VERSION 5.7 ;
BUSBITCHARS "[]" ;
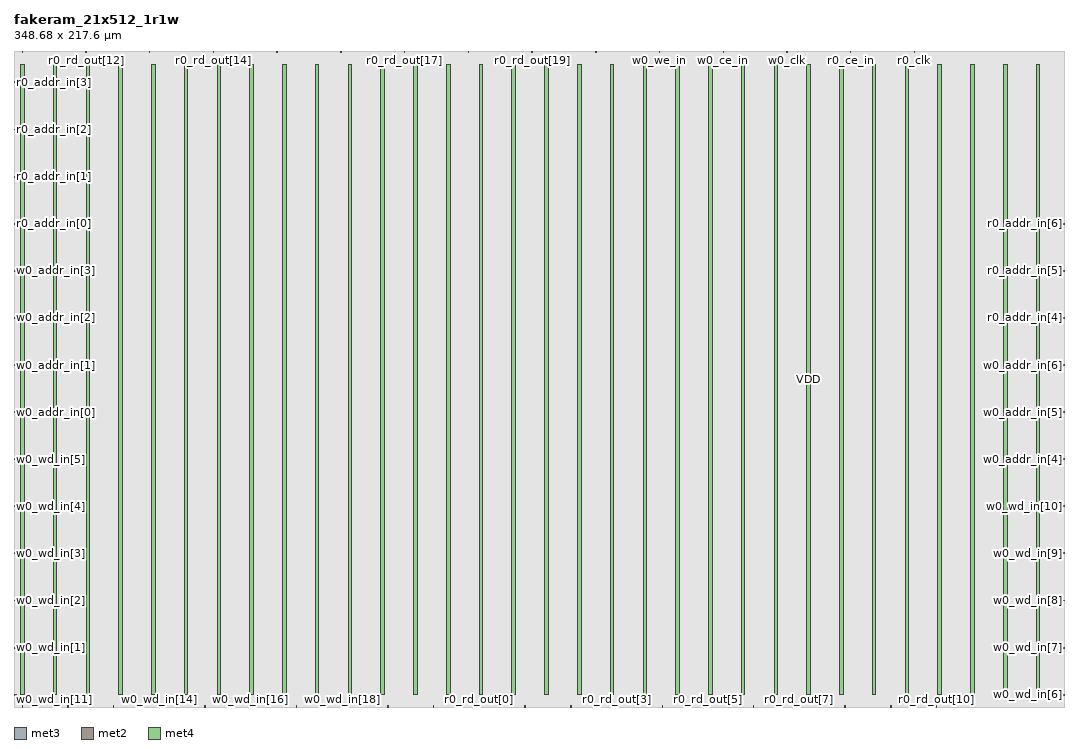
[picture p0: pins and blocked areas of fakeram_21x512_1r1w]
MACRO fakeram_21x512_1r1w
  FOREIGN fakeram_21x512_1r1w 0 0 ;
  SYMMETRY X Y R90 ;
  SIZE 348.680 BY 217.600 ;
  CLASS BLOCK ;
  PIN w0_wd_in[0]
    DIRECTION INPUT ;
    USE SIGNAL ;
    SHAPE ABUTMENT ;
    PORT
      LAYER met3 ;
      RECT 0.000 3.930 0.900 4.230 ;
    END
  END w0_wd_in[0]
  PIN w0_wd_in[1]
    DIRECTION INPUT ;
    USE SIGNAL ;
    SHAPE ABUTMENT ;
    PORT
      LAYER met3 ;
      RECT 0.000 19.570 0.900 19.870 ;
    END
  END w0_wd_in[1]
  PIN w0_wd_in[2]
    DIRECTION INPUT ;
    USE SIGNAL ;
    SHAPE ABUTMENT ;
    PORT
      LAYER met3 ;
      RECT 0.000 35.210 0.900 35.510 ;
    END
  END w0_wd_in[2]
  PIN w0_wd_in[3]
    DIRECTION INPUT ;
    USE SIGNAL ;
    SHAPE ABUTMENT ;
    PORT
      LAYER met3 ;
      RECT 0.000 50.850 0.900 51.150 ;
    END
  END w0_wd_in[3]
  PIN w0_wd_in[4]
    DIRECTION INPUT ;
    USE SIGNAL ;
    SHAPE ABUTMENT ;
    PORT
      LAYER met3 ;
      RECT 0.000 66.490 0.900 66.790 ;
    END
  END w0_wd_in[4]
  PIN w0_wd_in[5]
    DIRECTION INPUT ;
    USE SIGNAL ;
    SHAPE ABUTMENT ;
    PORT
      LAYER met3 ;
      RECT 0.000 82.130 0.900 82.430 ;
    END
  END w0_wd_in[5]
  PIN w0_wd_in[6]
    DIRECTION INPUT ;
    USE SIGNAL ;
    SHAPE ABUTMENT ;
    PORT
      LAYER met3 ;
      RECT 347.780 3.930 348.680 4.230 ;
    END
  END w0_wd_in[6]
  PIN w0_wd_in[7]
    DIRECTION INPUT ;
    USE SIGNAL ;
    SHAPE ABUTMENT ;
    PORT
      LAYER met3 ;
      RECT 347.780 19.570 348.680 19.870 ;
    END
  END w0_wd_in[7]
  PIN w0_wd_in[8]
    DIRECTION INPUT ;
    USE SIGNAL ;
    SHAPE ABUTMENT ;
    PORT
      LAYER met3 ;
      RECT 347.780 35.210 348.680 35.510 ;
    END
  END w0_wd_in[8]
  PIN w0_wd_in[9]
    DIRECTION INPUT ;
    USE SIGNAL ;
    SHAPE ABUTMENT ;
    PORT
      LAYER met3 ;
      RECT 347.780 50.850 348.680 51.150 ;
    END
  END w0_wd_in[9]
  PIN w0_wd_in[10]
    DIRECTION INPUT ;
    USE SIGNAL ;
    SHAPE ABUTMENT ;
    PORT
      LAYER met3 ;
      RECT 347.780 66.490 348.680 66.790 ;
    END
  END w0_wd_in[10]
  PIN w0_wd_in[11]
    DIRECTION INPUT ;
    USE SIGNAL ;
    SHAPE ABUTMENT ;
    PORT
      LAYER met2 ;
      RECT 2.690 0.000 2.830 0.420 ;
    END
  END w0_wd_in[11]
  PIN w0_wd_in[12]
    DIRECTION INPUT ;
    USE SIGNAL ;
    SHAPE ABUTMENT ;
    PORT
      LAYER met2 ;
      RECT 17.870 0.000 18.010 0.420 ;
    END
  END w0_wd_in[12]
  PIN w0_wd_in[13]
    DIRECTION INPUT ;
    USE SIGNAL ;
    SHAPE ABUTMENT ;
    PORT
      LAYER met2 ;
      RECT 33.050 0.000 33.190 0.420 ;
    END
  END w0_wd_in[13]
  PIN w0_wd_in[14]
    DIRECTION INPUT ;
    USE SIGNAL ;
    SHAPE ABUTMENT ;
    PORT
      LAYER met2 ;
      RECT 48.230 0.000 48.370 0.420 ;
    END
  END w0_wd_in[14]
  PIN w0_wd_in[15]
    DIRECTION INPUT ;
    USE SIGNAL ;
    SHAPE ABUTMENT ;
    PORT
      LAYER met2 ;
      RECT 63.410 0.000 63.550 0.420 ;
    END
  END w0_wd_in[15]
  PIN w0_wd_in[16]
    DIRECTION INPUT ;
    USE SIGNAL ;
    SHAPE ABUTMENT ;
    PORT
      LAYER met2 ;
      RECT 78.590 0.000 78.730 0.420 ;
    END
  END w0_wd_in[16]
  PIN w0_wd_in[17]
    DIRECTION INPUT ;
    USE SIGNAL ;
    SHAPE ABUTMENT ;
    PORT
      LAYER met2 ;
      RECT 93.770 0.000 93.910 0.420 ;
    END
  END w0_wd_in[17]
  PIN w0_wd_in[18]
    DIRECTION INPUT ;
    USE SIGNAL ;
    SHAPE ABUTMENT ;
    PORT
      LAYER met2 ;
      RECT 108.950 0.000 109.090 0.420 ;
    END
  END w0_wd_in[18]
  PIN w0_wd_in[19]
    DIRECTION INPUT ;
    USE SIGNAL ;
    SHAPE ABUTMENT ;
    PORT
      LAYER met2 ;
      RECT 124.130 0.000 124.270 0.420 ;
    END
  END w0_wd_in[19]
  PIN w0_wd_in[20]
    DIRECTION INPUT ;
    USE SIGNAL ;
    SHAPE ABUTMENT ;
    PORT
      LAYER met2 ;
      RECT 139.310 0.000 139.450 0.420 ;
    END
  END w0_wd_in[20]
  PIN r0_rd_out[0]
    DIRECTION OUTPUT ;
    USE SIGNAL ;
    SHAPE ABUTMENT ;
    PORT
      LAYER met2 ;
      RECT 154.490 0.000 154.630 0.420 ;
    END
  END r0_rd_out[0]
  PIN r0_rd_out[1]
    DIRECTION OUTPUT ;
    USE SIGNAL ;
    SHAPE ABUTMENT ;
    PORT
      LAYER met2 ;
      RECT 169.670 0.000 169.810 0.420 ;
    END
  END r0_rd_out[1]
  PIN r0_rd_out[2]
    DIRECTION OUTPUT ;
    USE SIGNAL ;
    SHAPE ABUTMENT ;
    PORT
      LAYER met2 ;
      RECT 184.850 0.000 184.990 0.420 ;
    END
  END r0_rd_out[2]
  PIN r0_rd_out[3]
    DIRECTION OUTPUT ;
    USE SIGNAL ;
    SHAPE ABUTMENT ;
    PORT
      LAYER met2 ;
      RECT 200.030 0.000 200.170 0.420 ;
    END
  END r0_rd_out[3]
  PIN r0_rd_out[4]
    DIRECTION OUTPUT ;
    USE SIGNAL ;
    SHAPE ABUTMENT ;
    PORT
      LAYER met2 ;
      RECT 215.210 0.000 215.350 0.420 ;
    END
  END r0_rd_out[4]
  PIN r0_rd_out[5]
    DIRECTION OUTPUT ;
    USE SIGNAL ;
    SHAPE ABUTMENT ;
    PORT
      LAYER met2 ;
      RECT 230.390 0.000 230.530 0.420 ;
    END
  END r0_rd_out[5]
  PIN r0_rd_out[6]
    DIRECTION OUTPUT ;
    USE SIGNAL ;
    SHAPE ABUTMENT ;
    PORT
      LAYER met2 ;
      RECT 245.570 0.000 245.710 0.420 ;
    END
  END r0_rd_out[6]
  PIN r0_rd_out[7]
    DIRECTION OUTPUT ;
    USE SIGNAL ;
    SHAPE ABUTMENT ;
    PORT
      LAYER met2 ;
      RECT 260.750 0.000 260.890 0.420 ;
    END
  END r0_rd_out[7]
  PIN r0_rd_out[8]
    DIRECTION OUTPUT ;
    USE SIGNAL ;
    SHAPE ABUTMENT ;
    PORT
      LAYER met2 ;
      RECT 275.930 0.000 276.070 0.420 ;
    END
  END r0_rd_out[8]
  PIN r0_rd_out[9]
    DIRECTION OUTPUT ;
    USE SIGNAL ;
    SHAPE ABUTMENT ;
    PORT
      LAYER met2 ;
      RECT 291.110 0.000 291.250 0.420 ;
    END
  END r0_rd_out[9]
  PIN r0_rd_out[10]
    DIRECTION OUTPUT ;
    USE SIGNAL ;
    SHAPE ABUTMENT ;
    PORT
      LAYER met2 ;
      RECT 306.290 0.000 306.430 0.420 ;
    END
  END r0_rd_out[10]
  PIN r0_rd_out[11]
    DIRECTION OUTPUT ;
    USE SIGNAL ;
    SHAPE ABUTMENT ;
    PORT
      LAYER met2 ;
      RECT 2.690 217.180 2.830 217.600 ;
    END
  END r0_rd_out[11]
  PIN r0_rd_out[12]
    DIRECTION OUTPUT ;
    USE SIGNAL ;
    SHAPE ABUTMENT ;
    PORT
      LAYER met2 ;
      RECT 23.850 217.180 23.990 217.600 ;
    END
  END r0_rd_out[12]
  PIN r0_rd_out[13]
    DIRECTION OUTPUT ;
    USE SIGNAL ;
    SHAPE ABUTMENT ;
    PORT
      LAYER met2 ;
      RECT 45.010 217.180 45.150 217.600 ;
    END
  END r0_rd_out[13]
  PIN r0_rd_out[14]
    DIRECTION OUTPUT ;
    USE SIGNAL ;
    SHAPE ABUTMENT ;
    PORT
      LAYER met2 ;
      RECT 66.170 217.180 66.310 217.600 ;
    END
  END r0_rd_out[14]
  PIN r0_rd_out[15]
    DIRECTION OUTPUT ;
    USE SIGNAL ;
    SHAPE ABUTMENT ;
    PORT
      LAYER met2 ;
      RECT 87.330 217.180 87.470 217.600 ;
    END
  END r0_rd_out[15]
  PIN r0_rd_out[16]
    DIRECTION OUTPUT ;
    USE SIGNAL ;
    SHAPE ABUTMENT ;
    PORT
      LAYER met2 ;
      RECT 108.490 217.180 108.630 217.600 ;
    END
  END r0_rd_out[16]
  PIN r0_rd_out[17]
    DIRECTION OUTPUT ;
    USE SIGNAL ;
    SHAPE ABUTMENT ;
    PORT
      LAYER met2 ;
      RECT 129.650 217.180 129.790 217.600 ;
    END
  END r0_rd_out[17]
  PIN r0_rd_out[18]
    DIRECTION OUTPUT ;
    USE SIGNAL ;
    SHAPE ABUTMENT ;
    PORT
      LAYER met2 ;
      RECT 150.810 217.180 150.950 217.600 ;
    END
  END r0_rd_out[18]
  PIN r0_rd_out[19]
    DIRECTION OUTPUT ;
    USE SIGNAL ;
    SHAPE ABUTMENT ;
    PORT
      LAYER met2 ;
      RECT 171.970 217.180 172.110 217.600 ;
    END
  END r0_rd_out[19]
  PIN r0_rd_out[20]
    DIRECTION OUTPUT ;
    USE SIGNAL ;
    SHAPE ABUTMENT ;
    PORT
      LAYER met2 ;
      RECT 193.130 217.180 193.270 217.600 ;
    END
  END r0_rd_out[20]
  PIN w0_addr_in[0]
    DIRECTION INPUT ;
    USE SIGNAL ;
    SHAPE ABUTMENT ;
    PORT
      LAYER met3 ;
      RECT 0.000 97.770 0.900 98.070 ;
    END
  END w0_addr_in[0]
  PIN w0_addr_in[1]
    DIRECTION INPUT ;
    USE SIGNAL ;
    SHAPE ABUTMENT ;
    PORT
      LAYER met3 ;
      RECT 0.000 113.410 0.900 113.710 ;
    END
  END w0_addr_in[1]
  PIN w0_addr_in[2]
    DIRECTION INPUT ;
    USE SIGNAL ;
    SHAPE ABUTMENT ;
    PORT
      LAYER met3 ;
      RECT 0.000 129.050 0.900 129.350 ;
    END
  END w0_addr_in[2]
  PIN w0_addr_in[3]
    DIRECTION INPUT ;
    USE SIGNAL ;
    SHAPE ABUTMENT ;
    PORT
      LAYER met3 ;
      RECT 0.000 144.690 0.900 144.990 ;
    END
  END w0_addr_in[3]
  PIN w0_addr_in[4]
    DIRECTION INPUT ;
    USE SIGNAL ;
    SHAPE ABUTMENT ;
    PORT
      LAYER met3 ;
      RECT 347.780 82.130 348.680 82.430 ;
    END
  END w0_addr_in[4]
  PIN w0_addr_in[5]
    DIRECTION INPUT ;
    USE SIGNAL ;
    SHAPE ABUTMENT ;
    PORT
      LAYER met3 ;
      RECT 347.780 97.770 348.680 98.070 ;
    END
  END w0_addr_in[5]
  PIN w0_addr_in[6]
    DIRECTION INPUT ;
    USE SIGNAL ;
    SHAPE ABUTMENT ;
    PORT
      LAYER met3 ;
      RECT 347.780 113.410 348.680 113.710 ;
    END
  END w0_addr_in[6]
  PIN r0_addr_in[0]
    DIRECTION INPUT ;
    USE SIGNAL ;
    SHAPE ABUTMENT ;
    PORT
      LAYER met3 ;
      RECT 0.000 160.330 0.900 160.630 ;
    END
  END r0_addr_in[0]
  PIN r0_addr_in[1]
    DIRECTION INPUT ;
    USE SIGNAL ;
    SHAPE ABUTMENT ;
    PORT
      LAYER met3 ;
      RECT 0.000 175.970 0.900 176.270 ;
    END
  END r0_addr_in[1]
  PIN r0_addr_in[2]
    DIRECTION INPUT ;
    USE SIGNAL ;
    SHAPE ABUTMENT ;
    PORT
      LAYER met3 ;
      RECT 0.000 191.610 0.900 191.910 ;
    END
  END r0_addr_in[2]
  PIN r0_addr_in[3]
    DIRECTION INPUT ;
    USE SIGNAL ;
    SHAPE ABUTMENT ;
    PORT
      LAYER met3 ;
      RECT 0.000 207.250 0.900 207.550 ;
    END
  END r0_addr_in[3]
  PIN r0_addr_in[4]
    DIRECTION INPUT ;
    USE SIGNAL ;
    SHAPE ABUTMENT ;
    PORT
      LAYER met3 ;
      RECT 347.780 129.050 348.680 129.350 ;
    END
  END r0_addr_in[4]
  PIN r0_addr_in[5]
    DIRECTION INPUT ;
    USE SIGNAL ;
    SHAPE ABUTMENT ;
    PORT
      LAYER met3 ;
      RECT 347.780 144.690 348.680 144.990 ;
    END
  END r0_addr_in[5]
  PIN r0_addr_in[6]
    DIRECTION INPUT ;
    USE SIGNAL ;
    SHAPE ABUTMENT ;
    PORT
      LAYER met3 ;
      RECT 347.780 160.330 348.680 160.630 ;
    END
  END r0_addr_in[6]
  PIN w0_we_in
    DIRECTION INPUT ;
    USE SIGNAL ;
    SHAPE ABUTMENT ;
    PORT
      LAYER met2 ;
      RECT 214.290 217.180 214.430 217.600 ;
    END
  END w0_we_in
  PIN w0_ce_in
    DIRECTION INPUT ;
    USE SIGNAL ;
    SHAPE ABUTMENT ;
    PORT
      LAYER met2 ;
      RECT 235.450 217.180 235.590 217.600 ;
    END
  END w0_ce_in
  PIN w0_clk
    DIRECTION INPUT ;
    USE SIGNAL ;
    SHAPE ABUTMENT ;
    PORT
      LAYER met2 ;
      RECT 256.610 217.180 256.750 217.600 ;
    END
  END w0_clk
  PIN r0_ce_in
    DIRECTION INPUT ;
    USE SIGNAL ;
    SHAPE ABUTMENT ;
    PORT
      LAYER met2 ;
      RECT 277.770 217.180 277.910 217.600 ;
    END
  END r0_ce_in
  PIN r0_clk
    DIRECTION INPUT ;
    USE SIGNAL ;
    SHAPE ABUTMENT ;
    PORT
      LAYER met2 ;
      RECT 298.930 217.180 299.070 217.600 ;
    END
  END r0_clk
  PIN VSS
    DIRECTION INOUT ;
    USE GROUND ;
    PORT
      LAYER met4 ;
      RECT 2.160 4.080 3.360 213.520 ;
      RECT 13.040 4.080 14.240 213.520 ;
      RECT 23.920 4.080 25.120 213.520 ;
      RECT 34.800 4.080 36.000 213.520 ;
      RECT 45.680 4.080 46.880 213.520 ;
      RECT 56.560 4.080 57.760 213.520 ;
      RECT 67.440 4.080 68.640 213.520 ;
      RECT 78.320 4.080 79.520 213.520 ;
      RECT 89.200 4.080 90.400 213.520 ;
      RECT 100.080 4.080 101.280 213.520 ;
      RECT 110.960 4.080 112.160 213.520 ;
      RECT 121.840 4.080 123.040 213.520 ;
      RECT 132.720 4.080 133.920 213.520 ;
      RECT 143.600 4.080 144.800 213.520 ;
      RECT 154.480 4.080 155.680 213.520 ;
      RECT 165.360 4.080 166.560 213.520 ;
      RECT 176.240 4.080 177.440 213.520 ;
      RECT 187.120 4.080 188.320 213.520 ;
      RECT 198.000 4.080 199.200 213.520 ;
      RECT 208.880 4.080 210.080 213.520 ;
      RECT 219.760 4.080 220.960 213.520 ;
      RECT 230.640 4.080 231.840 213.520 ;
      RECT 241.520 4.080 242.720 213.520 ;
      RECT 252.400 4.080 253.600 213.520 ;
      RECT 263.280 4.080 264.480 213.520 ;
      RECT 274.160 4.080 275.360 213.520 ;
      RECT 285.040 4.080 286.240 213.520 ;
      RECT 295.920 4.080 297.120 213.520 ;
      RECT 306.800 4.080 308.000 213.520 ;
      RECT 317.680 4.080 318.880 213.520 ;
      RECT 328.560 4.080 329.760 213.520 ;
      RECT 339.440 4.080 340.640 213.520 ;
    END
  END VSS
  PIN VDD
    DIRECTION INOUT ;
    USE POWER ;
    PORT
      LAYER met4 ;
      RECT 2.160 4.080 3.360 213.520 ;
      RECT 13.040 4.080 14.240 213.520 ;
      RECT 23.920 4.080 25.120 213.520 ;
      RECT 34.800 4.080 36.000 213.520 ;
      RECT 45.680 4.080 46.880 213.520 ;
      RECT 56.560 4.080 57.760 213.520 ;
      RECT 67.440 4.080 68.640 213.520 ;
      RECT 78.320 4.080 79.520 213.520 ;
      RECT 89.200 4.080 90.400 213.520 ;
      RECT 100.080 4.080 101.280 213.520 ;
      RECT 110.960 4.080 112.160 213.520 ;
      RECT 121.840 4.080 123.040 213.520 ;
      RECT 132.720 4.080 133.920 213.520 ;
      RECT 143.600 4.080 144.800 213.520 ;
      RECT 154.480 4.080 155.680 213.520 ;
      RECT 165.360 4.080 166.560 213.520 ;
      RECT 176.240 4.080 177.440 213.520 ;
      RECT 187.120 4.080 188.320 213.520 ;
      RECT 198.000 4.080 199.200 213.520 ;
      RECT 208.880 4.080 210.080 213.520 ;
      RECT 219.760 4.080 220.960 213.520 ;
      RECT 230.640 4.080 231.840 213.520 ;
      RECT 241.520 4.080 242.720 213.520 ;
      RECT 252.400 4.080 253.600 213.520 ;
      RECT 263.280 4.080 264.480 213.520 ;
      RECT 274.160 4.080 275.360 213.520 ;
      RECT 285.040 4.080 286.240 213.520 ;
      RECT 295.920 4.080 297.120 213.520 ;
      RECT 306.800 4.080 308.000 213.520 ;
      RECT 317.680 4.080 318.880 213.520 ;
      RECT 328.560 4.080 329.760 213.520 ;
      RECT 339.440 4.080 340.640 213.520 ;
    END
  END VDD
  OBS
    LAYER met1 ;
    RECT 0 0 348.680 217.600 ;
    LAYER met2 ;
    RECT 0 0 348.680 217.600 ;
    LAYER met3 ;
    RECT 0 0 348.680 217.600 ;
    LAYER met4 ;
    RECT 0 0 348.680 217.600 ;
  END
END fakeram_21x512_1r1w

END LIBRARY
